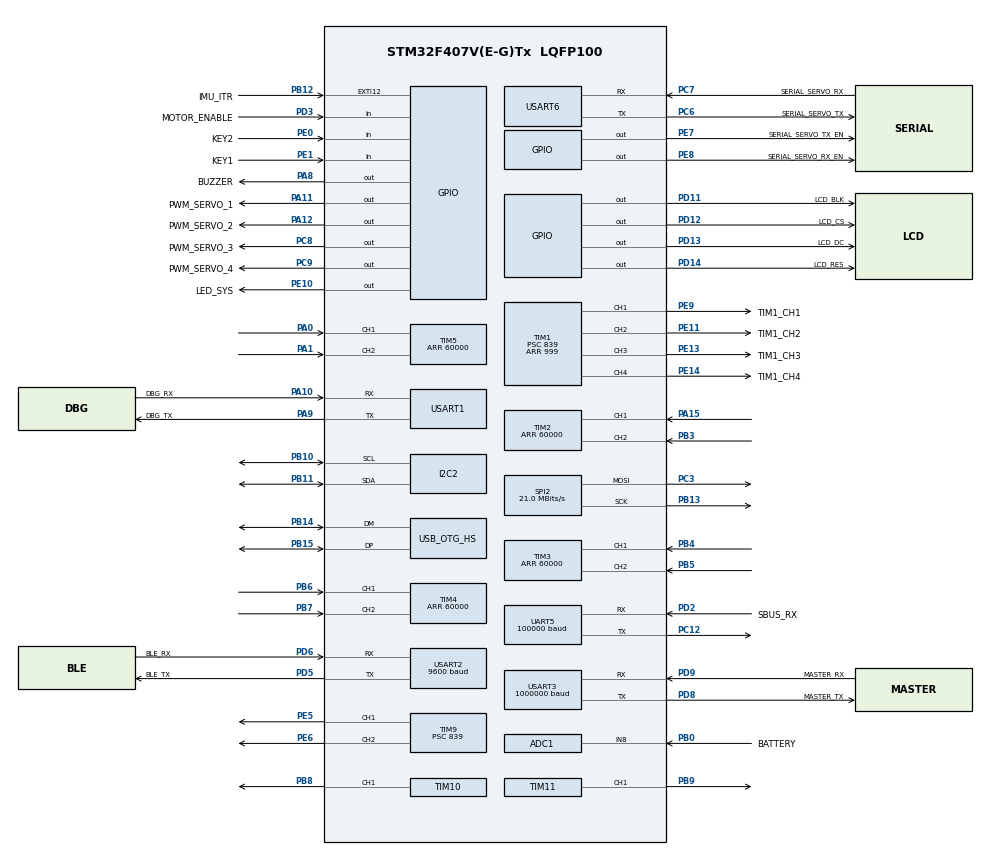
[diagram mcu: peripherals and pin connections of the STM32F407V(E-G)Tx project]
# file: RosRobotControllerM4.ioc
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ADC1.Channel-4\#ChannelRegularConversion=ADC_CHANNEL_VREFINT
ADC1.Channel-5\#ChannelRegularConversion=ADC_CHANNEL_8
ADC1.ClockPrescaler=ADC_CLOCK_SYNC_PCLK_DIV8
ADC1.ContinuousConvMode=DISABLE
ADC1.EOCSelection=ADC_EOC_SEQ_CONV
ADC1.NbrOfConversion=2
ADC1.NbrOfConversionFlag=1
ADC1.Rank-4\#ChannelRegularConversion=1
ADC1.Rank-5\#ChannelRegularConversion=2
ADC1.SamplingTime-4\#ChannelRegularConversion=ADC_SAMPLETIME_480CYCLES
ADC1.SamplingTime-5\#ChannelRegularConversion=ADC_SAMPLETIME_480CYCLES
ADC1.master=1
Dma.ADC1.8.Direction=DMA_PERIPH_TO_MEMORY
Dma.ADC1.8.FIFOMode=DMA_FIFOMODE_DISABLE
Dma.ADC1.8.Instance=DMA2_Stream0
Dma.ADC1.8.MemDataAlignment=DMA_MDATAALIGN_HALFWORD
Dma.ADC1.8.MemInc=DMA_MINC_ENABLE
Dma.ADC1.8.Mode=DMA_CIRCULAR
Dma.ADC1.8.PeriphDataAlignment=DMA_PDATAALIGN_HALFWORD
Dma.ADC1.8.PeriphInc=DMA_PINC_DISABLE
Dma.ADC1.8.Priority=DMA_PRIORITY_LOW
Dma.I2C2_RX.0.Direction=DMA_PERIPH_TO_MEMORY
Dma.I2C2_RX.0.FIFOMode=DMA_FIFOMODE_DISABLE
Dma.I2C2_RX.0.Instance=DMA1_Stream2
Dma.I2C2_RX.0.MemDataAlignment=DMA_MDATAALIGN_BYTE
Dma.I2C2_RX.0.MemInc=DMA_MINC_ENABLE
Dma.I2C2_RX.0.Mode=DMA_NORMAL
Dma.I2C2_RX.0.PeriphDataAlignment=DMA_PDATAALIGN_BYTE
Dma.I2C2_RX.0.PeriphInc=DMA_PINC_DISABLE
Dma.I2C2_RX.0.Priority=DMA_PRIORITY_VERY_HIGH
Dma.I2C2_TX.1.Direction=DMA_MEMORY_TO_PERIPH
Dma.I2C2_TX.1.FIFOMode=DMA_FIFOMODE_DISABLE
Dma.I2C2_TX.1.Instance=DMA1_Stream7
Dma.I2C2_TX.1.MemDataAlignment=DMA_MDATAALIGN_BYTE
Dma.I2C2_TX.1.MemInc=DMA_MINC_ENABLE
Dma.I2C2_TX.1.Mode=DMA_NORMAL
Dma.I2C2_TX.1.PeriphDataAlignment=DMA_PDATAALIGN_BYTE
Dma.I2C2_TX.1.PeriphInc=DMA_PINC_DISABLE
Dma.I2C2_TX.1.Priority=DMA_PRIORITY_VERY_HIGH
Dma.Request0=I2C2_RX
Dma.Request1=I2C2_TX
Dma.Request2=UART5_RX
Dma.Request3=USART3_RX
Dma.Request4=USART3_TX
Dma.Request5=SPI2_TX
Dma.Request6=USART2_RX
Dma.Request7=USART2_TX
Dma.Request8=ADC1
Dma.SPI2_TX.5.Direction=DMA_MEMORY_TO_PERIPH
Dma.SPI2_TX.5.FIFOMode=DMA_FIFOMODE_DISABLE
Dma.SPI2_TX.5.Instance=DMA1_Stream4
Dma.SPI2_TX.5.MemDataAlignment=DMA_MDATAALIGN_BYTE
Dma.SPI2_TX.5.MemInc=DMA_MINC_ENABLE
Dma.SPI2_TX.5.Mode=DMA_NORMAL
Dma.SPI2_TX.5.PeriphDataAlignment=DMA_PDATAALIGN_BYTE
Dma.SPI2_TX.5.PeriphInc=DMA_PINC_DISABLE
Dma.SPI2_TX.5.Priority=DMA_PRIORITY_LOW
Dma.UART5_RX.2.Direction=DMA_PERIPH_TO_MEMORY
Dma.UART5_RX.2.FIFOMode=DMA_FIFOMODE_DISABLE
Dma.UART5_RX.2.Instance=DMA1_Stream0
Dma.UART5_RX.2.MemDataAlignment=DMA_MDATAALIGN_BYTE
Dma.UART5_RX.2.MemInc=DMA_MINC_ENABLE
Dma.UART5_RX.2.Mode=DMA_CIRCULAR
Dma.UART5_RX.2.PeriphDataAlignment=DMA_PDATAALIGN_BYTE
Dma.UART5_RX.2.PeriphInc=DMA_PINC_DISABLE
Dma.UART5_RX.2.Priority=DMA_PRIORITY_MEDIUM
Dma.USART2_RX.6.Direction=DMA_PERIPH_TO_MEMORY
Dma.USART2_RX.6.FIFOMode=DMA_FIFOMODE_DISABLE
Dma.USART2_RX.6.Instance=DMA1_Stream5
Dma.USART2_RX.6.MemDataAlignment=DMA_MDATAALIGN_BYTE
Dma.USART2_RX.6.MemInc=DMA_MINC_ENABLE
Dma.USART2_RX.6.Mode=DMA_NORMAL
Dma.USART2_RX.6.PeriphDataAlignment=DMA_PDATAALIGN_BYTE
Dma.USART2_RX.6.PeriphInc=DMA_PINC_DISABLE
Dma.USART2_RX.6.Priority=DMA_PRIORITY_MEDIUM
Dma.USART2_TX.7.Direction=DMA_MEMORY_TO_PERIPH
Dma.USART2_TX.7.FIFOMode=DMA_FIFOMODE_DISABLE
Dma.USART2_TX.7.Instance=DMA1_Stream6
Dma.USART2_TX.7.MemDataAlignment=DMA_MDATAALIGN_BYTE
Dma.USART2_TX.7.MemInc=DMA_MINC_ENABLE
Dma.USART2_TX.7.Mode=DMA_NORMAL
Dma.USART2_TX.7.PeriphDataAlignment=DMA_PDATAALIGN_BYTE
Dma.USART2_TX.7.PeriphInc=DMA_PINC_DISABLE
Dma.USART2_TX.7.Priority=DMA_PRIORITY_MEDIUM
Dma.USART3_RX.3.Direction=DMA_PERIPH_TO_MEMORY
Dma.USART3_RX.3.FIFOMode=DMA_FIFOMODE_DISABLE
Dma.USART3_RX.3.Instance=DMA1_Stream1
Dma.USART3_RX.3.MemDataAlignment=DMA_MDATAALIGN_BYTE
Dma.USART3_RX.3.MemInc=DMA_MINC_ENABLE
Dma.USART3_RX.3.Mode=DMA_CIRCULAR
Dma.USART3_RX.3.PeriphDataAlignment=DMA_PDATAALIGN_BYTE
Dma.USART3_RX.3.PeriphInc=DMA_PINC_DISABLE
Dma.USART3_RX.3.Priority=DMA_PRIORITY_HIGH
Dma.USART3_TX.4.Direction=DMA_MEMORY_TO_PERIPH
Dma.USART3_TX.4.FIFOMode=DMA_FIFOMODE_DISABLE
Dma.USART3_TX.4.Instance=DMA1_Stream3
Dma.USART3_TX.4.MemDataAlignment=DMA_MDATAALIGN_BYTE
Dma.USART3_TX.4.MemInc=DMA_MINC_ENABLE
Dma.USART3_TX.4.Mode=DMA_NORMAL
Dma.USART3_TX.4.PeriphDataAlignment=DMA_PDATAALIGN_BYTE
Dma.USART3_TX.4.PeriphInc=DMA_PINC_DISABLE
Dma.USART3_TX.4.Priority=DMA_PRIORITY_HIGH
FREERTOS.BinarySemaphores01=packet_tx_idle,Static,packet_tx_ControlBlock;packet_rx_not_empty,Static,packet_rx_not_emptyControlBlock;mpu6050_data_ready,Static,mpu6050_data_readyControlBlock;sbus_data_ready_01_,Static,sbus_data_ready_01_ControlBlock;spi_tx_finished,Static,spi_tx_finishedControlBlock;bluetooth_tx_idle,Static,bluetooth_tx_idleControlBlock
FREERTOS.Events01=sbus_data_ready_event_,Static,sbus_data_ready_event_ControlBlock
FREERTOS.INCLUDE_vTaskCleanUpResources=1
FREERTOS.INCLUDE_xEventGroupSetBitFromISR=1
FREERTOS.Queues01=packet_tx_queue,64,void*,0,Static,packet_tx_queueBuffer,packet_tx_queueControlBlock;lvgl_event_queue,16,void*,0,Static,lvgl_event_queueBuffer,lvgl_event_queueControlBlock;moving_ctrl_queue,32,char,0,Static,moving_ctrl_queueBuffer,moving_ctrl_queueControlBlock;bluetooth_tx_queue,8,8,1,Static,bluetooth_tx_queueBuffer,bluetooth_tx_queueControlBlock
FREERTOS.Tasks01=defaultTask,8,128,StartDefaultTask,Default,NULL,Static,defaultTaskBuffer,defaultTaskControlBlock;imu_task,32,128,imu_task_entry,As weak,NULL,Static,imu_taskBuffer,imu_taskControlBlock;packet_tx_task,24,128,packet_tx_task_entry,As weak,NULL,Static,packet_tx_taskBuffer,packet_tx_taskControlBlock;packet_rx_task,24,256,packet_rx_task_entry,As weak,NULL,Static,packet_rx_taskBuffer,packet_rx_taskControlBlock;sbus_rx_task,24,128,sbus_rx_task_entry,As weak,NULL,Static,sbus_rx_taskBuffer,sbus_rx_taskControlBlock;gui_task,16,512,gui_task_entry,As weak,NULL,Static,gui_taskBuffer,gui_taskControlBlock;app_task,24,512,app_task_entry,As weak,NULL,Static,app_taskBuffer,app_taskControlBlock;bluetooth_task,24,128,bluetooth_task_entry,As weak,NULL,Static,bluetooth_taskBuffer,bluetooth_taskControlBlock
FREERTOS.Timers01=button_timer,button_timer_callback,osTimerPeriodic,As weak,NULL,Static,button_timerControlBlock;led_timer,led_timer_callback,osTimerPeriodic,As weak,NULL,Static,led_timerControlBlock;lvgl_timer,lvgl_timer_callback,osTimerPeriodic,As weak,NULL,Static,lvgl_timerControlBlock;buzzer_timer,buzzer_timer_callback,osTimerPeriodic,As weak,NULL,Static,buzzer_timerControlBlock;battery_check_timer,battery_check_timer_callback,osTimerPeriodic,As weak,NULL,Static,battery_check_timerControlBlock;IMU_read_timer,IMU_read_timer_callback,osTimerPeriodic,As weak,NULL,Static,IMU_read_timerControlBlock
FREERTOS.configENABLE_FPU=1
FREERTOS.configTIMER_QUEUE_LENGTH=10
FREERTOS.configTIMER_TASK_STACK_DEPTH=6144
FREERTOS.configTOTAL_HEAP_SIZE=12288
FREERTOS.configUSE_IDLE_HOOK=1
FREERTOS.configUSE_NEWLIB_REENTRANT=0
FREERTOS.configUSE_TICK_HOOK=1
I2C2.DutyCycle=I2C_DUTYCYCLE_16_9
I2C2.I2C_Mode=I2C_Fast
Mcu.Family=STM32F4
Mcu.Name=STM32F407V(E-G)Tx
Mcu.Package=LQFP100
NVIC.DMA1_Stream0_IRQn=true\:5\:0\:false\:true\:true\:1\:true\:false\:true\:true
NVIC.DMA1_Stream1_IRQn=true\:5\:0\:false\:true\:true\:2\:true\:false\:true\:true
NVIC.DMA1_Stream2_IRQn=true\:5\:0\:false\:true\:true\:3\:true\:false\:true\:true
NVIC.DMA1_Stream3_IRQn=true\:5\:0\:false\:true\:true\:4\:true\:false\:true\:true
NVIC.DMA1_Stream4_IRQn=true\:5\:0\:false\:false\:true\:true\:true\:true\:true
NVIC.DMA1_Stream5_IRQn=true\:5\:0\:false\:false\:true\:true\:true\:true\:true
NVIC.DMA1_Stream6_IRQn=true\:5\:0\:false\:false\:true\:true\:true\:true\:true
NVIC.DMA1_Stream7_IRQn=true\:5\:0\:false\:true\:true\:9\:true\:false\:true\:true
NVIC.EXTI15_10_IRQn=true\:5\:0\:false\:true\:true\:7\:true\:true\:false\:true
NVIC.OTG_HS_IRQn=true\:5\:0\:false\:false\:true\:true\:false\:true\:true
NVIC.PriorityGroup=NVIC_PRIORITYGROUP_4
NVIC.TIM2_IRQn=true\:5\:0\:false\:false\:true\:true\:true\:false\:true
NVIC.TIM3_IRQn=true\:5\:0\:false\:false\:true\:true\:true\:false\:true
NVIC.TIM4_IRQn=true\:5\:0\:false\:false\:true\:true\:true\:false\:true
NVIC.TIM5_IRQn=true\:5\:0\:false\:true\:true\:10\:true\:true\:false\:true
NVIC.TIM7_IRQn=true\:5\:0\:false\:true\:true\:12\:true\:true\:false\:true
NVIC.TIM8_BRK_TIM12_IRQn=true\:5\:0\:false\:false\:true\:true\:true\:false\:true
NVIC.TIM8_TRG_COM_TIM14_IRQn=true\:0\:0\:false\:false\:true\:false\:false\:true\:true
NVIC.TIM8_UP_TIM13_IRQn=true\:5\:0\:false\:true\:true\:8\:true\:true\:false\:true
NVIC.TimeBase=TIM8_TRG_COM_TIM14_IRQn
NVIC.TimeBaseIP=TIM14
NVIC.UART5_IRQn=true\:5\:0\:true\:true\:true\:11\:true\:true\:true\:true
NVIC.USART2_IRQn=true\:5\:0\:false\:true\:true\:5\:true\:true\:true\:true
NVIC.USART3_IRQn=true\:5\:0\:false\:true\:true\:6\:true\:true\:true\:true
NVIC.USART6_IRQn=true\:5\:0\:false\:true\:true\:13\:true\:true\:true\:true
PA0-WKUP.GPIO_PuPd=GPIO_PULLUP
PA0-WKUP.GPIO_Speed=GPIO_SPEED_FREQ_VERY_HIGH
PA0-WKUP.Signal=S_TIM5_CH1
PA1.GPIO_PuPd=GPIO_PULLUP
PA1.GPIO_Speed=GPIO_SPEED_FREQ_VERY_HIGH
PA1.Signal=S_TIM5_CH2
PA10.GPIO_Label=DBG_RX
PA10.Mode=Asynchronous
PA10.Signal=USART1_RX
PA11.GPIO_Label=PWM_SERVO_1
PA11.GPIO_Speed=GPIO_SPEED_FREQ_HIGH
PA11.PinState=GPIO_PIN_RESET
PA11.Signal=GPIO_Output
PA12.GPIO_Label=PWM_SERVO_2
PA12.GPIO_Speed=GPIO_SPEED_FREQ_HIGH
PA12.Signal=GPIO_Output
PA13.Signal=SYS_JTMS-SWDIO
PA14.Signal=SYS_JTCK-SWCLK
PA15.GPIO_PuPd=GPIO_PULLUP
PA15.GPIO_Speed=GPIO_SPEED_FREQ_VERY_HIGH
PA15.Signal=S_TIM2_CH1_ETR
PA8.GPIO_Label=BUZZER
PA8.GPIO_Speed=GPIO_SPEED_FREQ_VERY_HIGH
PA8.PinState=GPIO_PIN_RESET
PA8.Signal=GPIO_Output
PA9.GPIO_Label=DBG_TX
PA9.Mode=Asynchronous
PA9.Signal=USART1_TX
PB0.GPIO_Label=BATTERY
PB0.Signal=ADCx_IN8
PB10.GPIO_Pu=GPIO_PULLUP
PB10.Mode=I2C
PB10.Signal=I2C2_SCL
PB11.GPIO_Pu=GPIO_PULLUP
PB11.Mode=I2C
PB11.Signal=I2C2_SDA
PB12.GPIO_Label=IMU_ITR
PB12.Signal=GPXTI12
PB13.Mode=TX_Only_Simplex_Unidirect_Master
PB13.Signal=SPI2_SCK
PB14.Mode=Host_FS
PB14.Signal=USB_OTG_HS_DM
PB15.Mode=Host_FS
PB15.Signal=USB_OTG_HS_DP
PB3.GPIO_PuPd=GPIO_PULLUP
PB3.GPIO_Speed=GPIO_SPEED_FREQ_VERY_HIGH
PB3.Signal=S_TIM2_CH2
PB4.GPIO_Speed=GPIO_SPEED_FREQ_VERY_HIGH
PB4.Signal=S_TIM3_CH1
PB5.GPIO_Speed=GPIO_SPEED_FREQ_VERY_HIGH
PB5.Signal=S_TIM3_CH2
PB6.Signal=S_TIM4_CH1
PB7.Signal=S_TIM4_CH2
PB8.Signal=S_TIM10_CH1
PB9.GPIO_Speed=GPIO_SPEED_FREQ_HIGH
PB9.Signal=S_TIM11_CH1
PC12.Mode=Asynchronous
PC12.Signal=UART5_TX
PC3.Mode=TX_Only_Simplex_Unidirect_Master
PC3.Signal=SPI2_MOSI
PC6.GPIO_Label=SERIAL_SERVO_TX
PC6.Mode=Asynchronous
PC6.Signal=USART6_TX
PC7.GPIO_Label=SERIAL_SERVO_RX
PC7.Mode=Asynchronous
PC7.Signal=USART6_RX
PC8.GPIO_Label=PWM_SERVO_3
PC8.GPIO_Speed=GPIO_SPEED_FREQ_HIGH
PC8.PinState=GPIO_PIN_SET
PC8.Signal=GPIO_Output
PC9.GPIO_Label=PWM_SERVO_4
PC9.GPIO_Speed=GPIO_SPEED_FREQ_HIGH
PC9.Signal=GPIO_Output
PD11.GPIO_Label=LCD_BLK
PD11.GPIO_Speed=GPIO_SPEED_FREQ_VERY_HIGH
PD11.PinState=GPIO_PIN_SET
PD11.Signal=GPIO_Output
PD12.GPIO_Label=LCD_CS
PD12.GPIO_Speed=GPIO_SPEED_FREQ_VERY_HIGH
PD12.PinState=GPIO_PIN_SET
PD12.Signal=GPIO_Output
PD13.GPIO_Label=LCD_DC
PD13.GPIO_Speed=GPIO_SPEED_FREQ_VERY_HIGH
PD13.Signal=GPIO_Output
PD14.GPIO_Label=LCD_RES
PD14.GPIO_Speed=GPIO_SPEED_FREQ_VERY_HIGH
PD14.PinState=GPIO_PIN_SET
PD14.Signal=GPIO_Output
PD2.GPIO_Label=SBUS_RX
PD2.Mode=Asynchronous
PD2.Signal=UART5_RX
PD3.GPIO_Label=MOTOR_ENABLE
PD3.Signal=GPIO_Input
PD5.GPIO_Label=BLE_TX
PD5.Mode=Asynchronous
PD5.Signal=USART2_TX
PD6.GPIO_Label=BLE_RX
PD6.Mode=Asynchronous
PD6.Signal=USART2_RX
PD8.GPIO_Label=MASTER_TX
PD8.GPIO_PuPd=GPIO_NOPULL
PD8.Mode=Asynchronous
PD8.Signal=USART3_TX
PD9.GPIO_Label=MASTER_RX
PD9.GPIO_PuPd=GPIO_NOPULL
PD9.Mode=Asynchronous
PD9.Signal=USART3_RX
PE0.GPIO_Label=KEY2
PE0.Signal=GPIO_Input
PE1.GPIO_Label=KEY1
PE1.Signal=GPIO_Input
PE10.GPIO_Label=LED_SYS
PE10.GPIO_Speed=GPIO_SPEED_FREQ_MEDIUM
PE10.PinState=GPIO_PIN_SET
PE10.Signal=GPIO_Output
PE11.GPIO_Label=TIM1_CH2
PE11.GPIO_Speed=GPIO_SPEED_FREQ_HIGH
PE11.Signal=S_TIM1_CH2
PE13.GPIO_Label=TIM1_CH3
PE13.GPIO_Speed=GPIO_SPEED_FREQ_HIGH
PE13.Signal=S_TIM1_CH3
PE14.GPIO_Label=TIM1_CH4
PE14.GPIO_Speed=GPIO_SPEED_FREQ_HIGH
PE14.Signal=S_TIM1_CH4
PE5.Signal=S_TIM9_CH1
PE6.Signal=S_TIM9_CH2
PE7.GPIO_Label=SERIAL_SERVO_TX_EN
PE7.GPIO_Speed=GPIO_SPEED_FREQ_VERY_HIGH
PE7.Signal=GPIO_Output
PE8.GPIO_Label=SERIAL_SERVO_RX_EN
PE8.GPIO_Speed=GPIO_SPEED_FREQ_VERY_HIGH
PE8.Signal=GPIO_Output
PE9.GPIO_Label=TIM1_CH1
PE9.GPIO_Speed=GPIO_SPEED_FREQ_HIGH
PE9.Signal=S_TIM1_CH1
PH0-OSC_IN.Mode=HSE-External-Oscillator
PH0-OSC_IN.Signal=RCC_OSC_IN
PH1-OSC_OUT.Mode=HSE-External-Oscillator
PH1-OSC_OUT.Signal=RCC_OSC_OUT
ProjectManager.HeapSize=0x200
ProjectManager.StackSize=0x600
ProjectManager.TargetToolchain=STM32CubeIDE
RCC.48MHZClocksFreq_Value=48000000
RCC.AHBFreq_Value=168000000
RCC.APB1CLKDivider=RCC_HCLK_DIV4
RCC.APB1Freq_Value=42000000
RCC.APB1TimFreq_Value=84000000
RCC.APB2CLKDivider=RCC_HCLK_DIV2
RCC.APB2Freq_Value=84000000
RCC.APB2TimFreq_Value=168000000
RCC.CortexFreq_Value=168000000
RCC.EnbaleCSS=true
RCC.HCLKFreq_Value=168000000
RCC.HSE_VALUE=8000000
RCC.HSI_VALUE=16000000
RCC.LSE_VALUE=32768
RCC.PLLM=4
RCC.PLLN=168
RCC.PLLQ=7
RCC.SYSCLKFreq_VALUE=168000000
RCC.SYSCLKSource=RCC_SYSCLKSOURCE_PLLCLK
RCC.VCOOutputFreq_Value=336000000
SH.ADCx_IN8.0=ADC1_IN8,IN8
SH.S_TIM10_CH1.0=TIM10_CH1,PWM Generation1 CH1
SH.S_TIM11_CH1.0=TIM11_CH1,PWM Generation1 CH1
SH.S_TIM1_CH1.0=TIM1_CH1,PWM Generation1 CH1
SH.S_TIM1_CH2.0=TIM1_CH2,PWM Generation2 CH2
SH.S_TIM1_CH3.0=TIM1_CH3,PWM Generation3 CH3
SH.S_TIM1_CH4.0=TIM1_CH4,PWM Generation4 CH4
SH.S_TIM2_CH1_ETR.0=TIM2_CH1,Encoder_Interface
SH.S_TIM2_CH2.0=TIM2_CH2,Encoder_Interface
SH.S_TIM3_CH1.0=TIM3_CH1,Encoder_Interface
SH.S_TIM3_CH2.0=TIM3_CH2,Encoder_Interface
SH.S_TIM4_CH1.0=TIM4_CH1,Encoder_Interface
SH.S_TIM4_CH2.0=TIM4_CH2,Encoder_Interface
SH.S_TIM5_CH1.0=TIM5_CH1,Encoder_Interface
SH.S_TIM5_CH2.0=TIM5_CH2,Encoder_Interface
SH.S_TIM9_CH1.0=TIM9_CH1,PWM Generation1 CH1
SH.S_TIM9_CH2.0=TIM9_CH2,PWM Generation2 CH2
SPI2.BaudRatePrescaler=SPI_BAUDRATEPRESCALER_2
SPI2.CLKPhase=SPI_PHASE_1EDGE
SPI2.CLKPolarity=SPI_POLARITY_LOW
SPI2.CalculateBaudRate=21.0 MBits/s
SPI2.DataSize=SPI_DATASIZE_8BIT
SPI2.Direction=SPI_DIRECTION_2LINES
SPI2.FirstBit=SPI_FIRSTBIT_MSB
SPI2.Mode=SPI_MODE_MASTER
SPI2.VirtualType=VM_MASTER
TIM1.AutoReloadPreload=TIM_AUTORELOAD_PRELOAD_ENABLE
TIM1.Channel-PWM\ Generation1\ CH1=TIM_CHANNEL_1
TIM1.Channel-PWM\ Generation2\ CH2=TIM_CHANNEL_2
TIM1.Channel-PWM\ Generation3\ CH3=TIM_CHANNEL_3
TIM1.Channel-PWM\ Generation4\ CH4=TIM_CHANNEL_4
TIM1.OCFastMode_PWM-PWM\ Generation1\ CH1=TIM_OCFAST_ENABLE
TIM1.OCFastMode_PWM-PWM\ Generation2\ CH2=TIM_OCFAST_ENABLE
TIM1.OCFastMode_PWM-PWM\ Generation3\ CH3=TIM_OCFAST_ENABLE
TIM1.OCFastMode_PWM-PWM\ Generation4\ CH4=TIM_OCFAST_ENABLE
TIM1.Period=999
TIM1.Prescaler=839
TIM1.Pulse-PWM\ Generation1\ CH1=0
TIM1.Pulse-PWM\ Generation2\ CH2=0
TIM1.Pulse-PWM\ Generation3\ CH3=0
TIM1.Pulse-PWM\ Generation4\ CH4=0
TIM10.AutoReloadPreload=TIM_AUTORELOAD_PRELOAD_ENABLE
TIM10.Channel=TIM_CHANNEL_1
TIM10.OCFastMode_PWM=TIM_OCFAST_ENABLE
TIM10.Period=999
TIM10.Prescaler=839
TIM11.AutoReloadPreload=TIM_AUTORELOAD_PRELOAD_ENABLE
TIM11.Channel=TIM_CHANNEL_1
TIM11.OCFastMode_PWM=TIM_OCFAST_ENABLE
TIM11.Period=999
TIM11.Prescaler=839
TIM11.Pulse=0
TIM12.AutoReloadPreload=TIM_AUTORELOAD_PRELOAD_ENABLE
TIM12.Channel-Output\ Compare1\ No\ Output=TIM_CHANNEL_1
TIM12.OC1Preload=ENABLE
TIM12.OCMode_1=TIM_OCMODE_TIMING
TIM12.Period=99
TIM12.Prescaler=839
TIM12.Pulse-Output\ Compare1\ No\ Output=50
TIM13.AutoReloadPreload=TIM_AUTORELOAD_PRELOAD_ENABLE
TIM13.Channel=TIM_CHANNEL_1
TIM13.OC1Preload=DISABLE
TIM13.Period=4999
TIM13.Prescaler=83
TIM13.Pulse=0
TIM2.AutoReloadPreload=TIM_AUTORELOAD_PRELOAD_ENABLE
TIM2.EncoderMode=TIM_ENCODERMODE_TI12
TIM2.Period=60000
TIM3.AutoReloadPreload=TIM_AUTORELOAD_PRELOAD_ENABLE
TIM3.EncoderMode=TIM_ENCODERMODE_TI12
TIM3.Period=60000
TIM4.AutoReloadPreload=TIM_AUTORELOAD_PRELOAD_ENABLE
TIM4.EncoderMode=TIM_ENCODERMODE_TI12
TIM4.Period=60000
TIM5.AutoReloadPreload=TIM_AUTORELOAD_PRELOAD_ENABLE
TIM5.EncoderMode=TIM_ENCODERMODE_TI12
TIM5.Period=60000
TIM7.AutoReloadPreload=TIM_AUTORELOAD_PRELOAD_ENABLE
TIM7.Period=9999
TIM7.Prescaler=83
TIM9.AutoReloadPreload=TIM_AUTORELOAD_PRELOAD_ENABLE
TIM9.Channel-PWM\ Generation1\ CH1=TIM_CHANNEL_1
TIM9.Channel-PWM\ Generation2\ CH2=TIM_CHANNEL_2
TIM9.OCFastMode_PWM-PWM\ Generation1\ CH1=TIM_OCFAST_ENABLE
TIM9.OCFastMode_PWM-PWM\ Generation2\ CH2=TIM_OCFAST_ENABLE
TIM9.Period=999
TIM9.Prescaler=839
UART5.BaudRate=100000
UART5.Mode=MODE_RX
UART5.Parity=PARITY_EVEN
UART5.StopBits=UART_STOPBITS_2
UART5.VirtualMode=Asynchronous
UART5.WordLength=WORDLENGTH_9B
USART1.VirtualMode=VM_ASYNC
USART2.BaudRate=9600
USART2.VirtualMode=VM_ASYNC
USART3.BaudRate=1000000
USART3.VirtualMode=VM_ASYNC
USART6.VirtualMode=VM_ASYNC
USB_HOST.USBH_DEBUG_LEVEL-HID_HS=0
USB_HOST.USBH_HandleTypeDef-HID_HS=hUsbHostHS
USB_HOST.USBH_KEEP_CFG_DESCRIPTOR-HID_HS=1
USB_HOST.USBH_MAX_DATA_BUFFER-HID_HS=512
USB_HOST.USBH_MAX_NUM_CONFIGURATION-HID_HS=2
USB_HOST.USBH_MAX_NUM_ENDPOINTS-HID_HS=2
USB_HOST.USBH_MAX_NUM_INTERFACES-HID_HS=2
USB_HOST.USBH_MAX_NUM_SUPPORTED_CLASS-HID_HS=1
USB_HOST.USBH_MAX_SIZE_CONFIGURATION-HID_HS=512
USB_HOST.USBH_PROCESS_PRIO-HID_HS=osPriorityNormal
USB_HOST.USBH_PROCESS_STACK_SIZE-HID_HS=2048
USB_HOST.VirtualModeHS=Hid
USB_OTG_HS.Sof_enable-Host_FS=DISABLE
USB_OTG_HS.VirtualMode-Host_FS=Host_FS
USB_OTG_HS.dma_enable-Host_FS=DISABLE
VP_ADC1_Vref_Input.Mode=IN-Vrefint
VP_CRC_VS_CRC.Mode=CRC_Activate
VP_FREERTOS_VS_CMSIS_V2.Mode=CMSIS_V2
VP_SYS_VS_tim14.Mode=TIM14
VP_TIM10_VS_ClockSourceINT.Mode=Enable_Timer
VP_TIM11_VS_ClockSourceINT.Mode=Enable_Timer
VP_TIM12_VS_ClockSourceINT.Mode=Internal
VP_TIM12_VS_no_output1.Mode=Output Compare1 No Output
VP_TIM13_VS_ClockSourceINT.Mode=Enable_Timer
VP_TIM13_VS_no_output1.Mode=Output Compare1 No Output
VP_TIM1_VS_ClockSourceINT.Mode=Internal
VP_TIM7_VS_ClockSourceINT.Mode=Enable_Timer
VP_TIM9_VS_ClockSourceINT.Mode=Internal
VP_USB_HOST_VS_USB_HOST_HID_HS.Mode=HID_HS
board=custom

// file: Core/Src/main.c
/* USER CODE BEGIN Header */
/**
  ******************************************************************************
  * @file           : main.c
  * @brief          : Main program body
  ******************************************************************************
  * @attention
  *
  * <h2><center>&copy; Copyright (c) 2023 STMicroelectronics.
  * All rights reserved.</center></h2>
  *
  * This software component is licensed by ST under BSD 3-Clause license,
  * the "License"; You may not use this file except in compliance with the
  * License. You may obtain a copy of the License at:
  *                        opensource.org/licenses/BSD-3-Clause
  *
  * ********************************************
  *   main()函数，单片机入口函数
  *
  *   ! ! ! 注意
  *   该工程使用了 FreeRTOS系统
  *   用户的入口函数在 Hiwonder/System文件夹中的app.c文件中的app_task_entry()线程任务�?
  *   �?要其他线程任务，则需创建其他线程（建议在STM32CubeMX软件中创建）
  *
  *   ! ! ! 注意
  *   在CubeMX中创建的文件中，
  *   用户程序与注�? 都需要写在以下注释的中间，才不会在使用CubeMX更改配置之后，导致用户程序被覆盖�? !!!
  *   (若不使用CubeMX软件，则可跳过该�?)
  *
  *   / * USER CODE BEGIN xxx * /
  *   //用户程序
  *   / * USER CODE END xxx * /
  *
  *
  * ********************************************
  *
  ******************************************************************************
  */
/* USER CODE END Header */
#include "main.h"
#include "cmsis_os.h"
#include "adc.h"
#include "crc.h"
#include "dma.h"
#include "i2c.h"
#include "spi.h"
#include "tim.h"
#include "usart.h"
#include "usb_host.h"
#include "gpio.h"

/* USER CODE BEGIN Includes */
#include "lwmem_porting.h"
#include "log.h"
#include <stdio.h>
/* USER CODE END Includes */

void SystemClock_Config(void);
void MX_FREERTOS_Init(void);
static void MX_NVIC_Init(void);

int main(void)
{
  /* USER CODE BEGIN 1 */
  //��־��ӡ���ܳ�ʼ��
  LOG_INIT();
  lwmem_assignmem(lwmem_regions);  /* ��̬�ڴ��ʼ�� */
  /* USER CODE END 1 */

  /* MCU Configuration--------------------------------------------------------*/

  /* Reset of all peripherals, Initializes the Flash interface and the Systick. */
  HAL_Init();

  /* Configure the system clock */
  SystemClock_Config();

  /* USER CODE BEGIN SysInit */
    //����IIC1
    __HAL_RCC_I2C1_CLK_ENABLE();
    //����DMA����
    __HAL_RCC_DMA1_CLK_ENABLE();
  /* USER CODE END SysInit */

  /* Initialize all configured peripherals */
  MX_GPIO_Init();
  MX_DMA_Init();
  MX_USART1_UART_Init();
  MX_SPI2_Init();
  MX_TIM1_Init();
  MX_TIM2_Init();
  MX_TIM5_Init();
  MX_TIM9_Init();
  MX_TIM10_Init();
  MX_TIM11_Init();
  MX_I2C2_Init();
  MX_UART5_Init();
  MX_USART2_UART_Init();
  MX_USART3_UART_Init();
  MX_USART6_UART_Init();
  MX_TIM7_Init();
  MX_TIM3_Init();
  MX_TIM4_Init();
  MX_TIM13_Init();
  MX_CRC_Init();
  MX_TIM12_Init();
  MX_ADC1_Init();

  // 1. USB 전원 공급용 유력 후보 핀들을 출력으로 설정
  GPIO_InitTypeDef GPIO_InitStruct = {0};
  __HAL_RCC_GPIOC_CLK_ENABLE();
  __HAL_RCC_GPIOH_CLK_ENABLE();

  MX_USB_HOST_Init();

  /* Initialize interrupts */
  MX_NVIC_Init();
  /* USER CODE BEGIN 2 */
  //��ӡ��Ϣ����printf()�������÷�һ�����ܹ����ݵȼ�����������־���
  LOG_DEBUG("Start...\r\n");
  /* USER CODE END 2 */

  /* Init scheduler */
  osKernelInitialize();  /* Call init function for freertos objects (in freertos.c) */
  MX_FREERTOS_Init();

  /* Start scheduler */
  osKernelStart();
  /* We should never get here as control is now taken by the scheduler */
  /* Infinite loop */
    while (1) {

    }
}

void SystemClock_Config(void)
{
  RCC_OscInitTypeDef RCC_OscInitStruct = {0};
  RCC_ClkInitTypeDef RCC_ClkInitStruct = {0};

  /** Configure the main internal regulator output voltage
  */
  __HAL_RCC_PWR_CLK_ENABLE();
  __HAL_PWR_VOLTAGESCALING_CONFIG(PWR_REGULATOR_VOLTAGE_SCALE1);

  /** Initializes the RCC Oscillators according to the specified parameters
  * in the RCC_OscInitTypeDef structure.
  */
  RCC_OscInitStruct.OscillatorType = RCC_OSCILLATORTYPE_HSE;
  RCC_OscInitStruct.HSEState = RCC_HSE_ON;
  RCC_OscInitStruct.PLL.PLLState = RCC_PLL_ON;
  RCC_OscInitStruct.PLL.PLLSource = RCC_PLLSOURCE_HSE;
  RCC_OscInitStruct.PLL.PLLM = 6;
  RCC_OscInitStruct.PLL.PLLN = 168;
  RCC_OscInitStruct.PLL.PLLP = RCC_PLLP_DIV2;
  RCC_OscInitStruct.PLL.PLLQ = 7;
  if (HAL_RCC_OscConfig(&RCC_OscInitStruct) != HAL_OK)
  {
    Error_Handler();
  }

  /** Initializes the CPU, AHB and APB buses clocks
  */
  RCC_ClkInitStruct.ClockType = RCC_CLOCKTYPE_HCLK|RCC_CLOCKTYPE_SYSCLK
                              |RCC_CLOCKTYPE_PCLK1|RCC_CLOCKTYPE_PCLK2;
  RCC_ClkInitStruct.SYSCLKSource = RCC_SYSCLKSOURCE_PLLCLK;
  RCC_ClkInitStruct.AHBCLKDivider = RCC_SYSCLK_DIV1;
  RCC_ClkInitStruct.APB1CLKDivider = RCC_HCLK_DIV4;
  RCC_ClkInitStruct.APB2CLKDivider = RCC_HCLK_DIV2;

  if (HAL_RCC_ClockConfig(&RCC_ClkInitStruct, FLASH_LATENCY_5) != HAL_OK)
  {
    Error_Handler();
  }

  /** Enables the Clock Security System
  */
  HAL_RCC_EnableCSS();
}

/**
  * @brief NVIC Configuration.
  * @retval None
  */
static void MX_NVIC_Init(void)
{
  /* DMA1_Stream0_IRQn interrupt configuration */
  HAL_NVIC_SetPriority(DMA1_Stream0_IRQn, 5, 0);
  HAL_NVIC_EnableIRQ(DMA1_Stream0_IRQn);
  /* DMA1_Stream1_IRQn interrupt configuration */
  HAL_NVIC_SetPriority(DMA1_Stream1_IRQn, 5, 0);
  HAL_NVIC_EnableIRQ(DMA1_Stream1_IRQn);
  /* DMA1_Stream2_IRQn interrupt configuration */
  HAL_NVIC_SetPriority(DMA1_Stream2_IRQn, 5, 0);
  HAL_NVIC_EnableIRQ(DMA1_Stream2_IRQn);
  /* DMA1_Stream3_IRQn interrupt configuration */
  HAL_NVIC_SetPriority(DMA1_Stream3_IRQn, 5, 0);
  HAL_NVIC_EnableIRQ(DMA1_Stream3_IRQn);
  /* USART2_IRQn interrupt configuration */
  HAL_NVIC_SetPriority(USART2_IRQn, 5, 0);
  HAL_NVIC_EnableIRQ(USART2_IRQn);
  /* USART3_IRQn interrupt configuration */
  HAL_NVIC_SetPriority(USART3_IRQn, 5, 0);
  HAL_NVIC_EnableIRQ(USART3_IRQn);
  /* EXTI15_10_IRQn interrupt configuration */
  HAL_NVIC_SetPriority(EXTI15_10_IRQn, 5, 0);
  HAL_NVIC_EnableIRQ(EXTI15_10_IRQn);
  /* TIM8_UP_TIM13_IRQn interrupt configuration */
  HAL_NVIC_SetPriority(TIM8_UP_TIM13_IRQn, 5, 0);
  HAL_NVIC_EnableIRQ(TIM8_UP_TIM13_IRQn);
  /* DMA1_Stream7_IRQn interrupt configuration */
  HAL_NVIC_SetPriority(DMA1_Stream7_IRQn, 5, 0);
  HAL_NVIC_EnableIRQ(DMA1_Stream7_IRQn);
  /* TIM5_IRQn interrupt configuration */
  HAL_NVIC_SetPriority(TIM5_IRQn, 5, 0);
  HAL_NVIC_EnableIRQ(TIM5_IRQn);
  /* UART5_IRQn interrupt configuration */
  HAL_NVIC_SetPriority(UART5_IRQn, 5, 0);
  HAL_NVIC_EnableIRQ(UART5_IRQn);
  /* TIM7_IRQn interrupt configuration */
  HAL_NVIC_SetPriority(TIM7_IRQn, 5, 0);
  HAL_NVIC_EnableIRQ(TIM7_IRQn);
  /* USART6_IRQn interrupt configuration */
  HAL_NVIC_SetPriority(USART6_IRQn, 5, 0);
  HAL_NVIC_EnableIRQ(USART6_IRQn);
}

void HAL_TIM_PeriodElapsedCallback(TIM_HandleTypeDef *htim)
{
  if (htim->Instance == TIM14) {
    HAL_IncTick();
  }
}

void Error_Handler(void)
{
    __disable_irq();
    while (1) {
    }
}

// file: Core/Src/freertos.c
/* USER CODE BEGIN Header */
/**
  ******************************************************************************
  * File Name          : freertos.c
  * Description        : Code for freertos applications
  ******************************************************************************
  * @attention
  *
  * <h2><center>&copy; Copyright (c) 2023 STMicroelectronics.
  * All rights reserved.</center></h2>
  *
  * This software component is licensed by ST under Ultimate Liberty license
  * SLA0044, the "License"; You may not use this file except in compliance with
  * the License. You may obtain a copy of the License at:
  *                             www.st.com/SLA0044
  *
  ******************************************************************************
  */
/* USER CODE END Header */

#include "FreeRTOS.h"
#include "task.h"
#include "main.h"
#include "cmsis_os.h"

/* USER CODE BEGIN Includes */
#include "lvgl.h"
/* USER CODE END Includes */

typedef StaticTask_t osStaticThreadDef_t;
typedef StaticQueue_t osStaticMessageQDef_t;
typedef StaticTimer_t osStaticTimerDef_t;
typedef StaticEventGroup_t osStaticEventGroupDef_t;

/* Definitions for defaultTask */
osThreadId_t defaultTaskHandle;
uint32_t defaultTaskBuffer[ 128 ];
osStaticThreadDef_t defaultTaskControlBlock;
const osThreadAttr_t defaultTask_attributes = {
  .name = "defaultTask",
  .cb_mem = &defaultTaskControlBlock,
  .cb_size = sizeof(defaultTaskControlBlock),
  .stack_mem = &defaultTaskBuffer[0],
  .stack_size = sizeof(defaultTaskBuffer),
  .priority = (osPriority_t) osPriorityLow,
};
/* Definitions for imu_task */
osThreadId_t imu_taskHandle;
uint32_t imu_taskBuffer[ 128 ];
osStaticThreadDef_t imu_taskControlBlock;
const osThreadAttr_t imu_task_attributes = {
  .name = "imu_task",
  .cb_mem = &imu_taskControlBlock,
  .cb_size = sizeof(imu_taskControlBlock),
  .stack_mem = &imu_taskBuffer[0],
  .stack_size = sizeof(imu_taskBuffer),
  .priority = (osPriority_t) osPriorityAboveNormal,
};
/* Definitions for packet_tx_task */
osThreadId_t packet_tx_taskHandle;
uint32_t packet_tx_taskBuffer[ 128 ];
osStaticThreadDef_t packet_tx_taskControlBlock;
const osThreadAttr_t packet_tx_task_attributes = {
  .name = "packet_tx_task",
  .cb_mem = &packet_tx_taskControlBlock,
  .cb_size = sizeof(packet_tx_taskControlBlock),
  .stack_mem = &packet_tx_taskBuffer[0],
  .stack_size = sizeof(packet_tx_taskBuffer),
  .priority = (osPriority_t) osPriorityNormal,
};
/* Definitions for packet_rx_task */
osThreadId_t packet_rx_taskHandle;
uint32_t packet_rx_taskBuffer[ 256 ];
osStaticThreadDef_t packet_rx_taskControlBlock;
const osThreadAttr_t packet_rx_task_attributes = {
  .name = "packet_rx_task",
  .cb_mem = &packet_rx_taskControlBlock,
  .cb_size = sizeof(packet_rx_taskControlBlock),
  .stack_mem = &packet_rx_taskBuffer[0],
  .stack_size = sizeof(packet_rx_taskBuffer),
  .priority = (osPriority_t) osPriorityNormal,
};
/* Definitions for sbus_rx_task */
osThreadId_t sbus_rx_taskHandle;
uint32_t sbus_rx_taskBuffer[ 128 ];
osStaticThreadDef_t sbus_rx_taskControlBlock;
const osThreadAttr_t sbus_rx_task_attributes = {
  .name = "sbus_rx_task",
  .cb_mem = &sbus_rx_taskControlBlock,
  .cb_size = sizeof(sbus_rx_taskControlBlock),
  .stack_mem = &sbus_rx_taskBuffer[0],
  .stack_size = sizeof(sbus_rx_taskBuffer),
  .priority = (osPriority_t) osPriorityNormal,
};
/* Definitions for gui_task */
osThreadId_t gui_taskHandle;
uint32_t gui_taskBuffer[ 512 ];
osStaticThreadDef_t gui_taskControlBlock;
const osThreadAttr_t gui_task_attributes = {
  .name = "gui_task",
  .cb_mem = &gui_taskControlBlock,
  .cb_size = sizeof(gui_taskControlBlock),
  .stack_mem = &gui_taskBuffer[0],
  .stack_size = sizeof(gui_taskBuffer),
  .priority = (osPriority_t) osPriorityBelowNormal,
};
/* Definitions for app_task */
osThreadId_t app_taskHandle;
uint32_t app_taskBuffer[ 512 ];
osStaticThreadDef_t app_taskControlBlock;
const osThreadAttr_t app_task_attributes = {
  .name = "app_task",
  .cb_mem = &app_taskControlBlock,
  .cb_size = sizeof(app_taskControlBlock),
  .stack_mem = &app_taskBuffer[0],
  .stack_size = sizeof(app_taskBuffer),
  .priority = (osPriority_t) osPriorityNormal,
};
/* Definitions for bluetooth_task */
osThreadId_t bluetooth_taskHandle;
uint32_t bluetooth_taskBuffer[ 128 ];
osStaticThreadDef_t bluetooth_taskControlBlock;
const osThreadAttr_t bluetooth_task_attributes = {
  .name = "bluetooth_task",
  .cb_mem = &bluetooth_taskControlBlock,
  .cb_size = sizeof(bluetooth_taskControlBlock),
  .stack_mem = &bluetooth_taskBuffer[0],
  .stack_size = sizeof(bluetooth_taskBuffer),
  .priority = (osPriority_t) osPriorityNormal,
};
/* Definitions for packet_tx_queue */
osMessageQueueId_t packet_tx_queueHandle;
uint8_t packet_tx_queueBuffer[ 64 * sizeof( void* ) ];
osStaticMessageQDef_t packet_tx_queueControlBlock;
const osMessageQueueAttr_t packet_tx_queue_attributes = {
  .name = "packet_tx_queue",
  .cb_mem = &packet_tx_queueControlBlock,
  .cb_size = sizeof(packet_tx_queueControlBlock),
  .mq_mem = &packet_tx_queueBuffer,
  .mq_size = sizeof(packet_tx_queueBuffer)
};
/* Definitions for lvgl_event_queue */
osMessageQueueId_t lvgl_event_queueHandle;
uint8_t lvgl_event_queueBuffer[ 16 * sizeof( void* ) ];
osStaticMessageQDef_t lvgl_event_queueControlBlock;
const osMessageQueueAttr_t lvgl_event_queue_attributes = {
  .name = "lvgl_event_queue",
  .cb_mem = &lvgl_event_queueControlBlock,
  .cb_size = sizeof(lvgl_event_queueControlBlock),
  .mq_mem = &lvgl_event_queueBuffer,
  .mq_size = sizeof(lvgl_event_queueBuffer)
};
/* Definitions for moving_ctrl_queue */
osMessageQueueId_t moving_ctrl_queueHandle;
uint8_t moving_ctrl_queueBuffer[ 32 * sizeof( char ) ];
osStaticMessageQDef_t moving_ctrl_queueControlBlock;
const osMessageQueueAttr_t moving_ctrl_queue_attributes = {
  .name = "moving_ctrl_queue",
  .cb_mem = &moving_ctrl_queueControlBlock,
  .cb_size = sizeof(moving_ctrl_queueControlBlock),
  .mq_mem = &moving_ctrl_queueBuffer,
  .mq_size = sizeof(moving_ctrl_queueBuffer)
};
/* Definitions for bluetooth_tx_queue */
osMessageQueueId_t bluetooth_tx_queueHandle;
uint8_t bluetooth_tx_queueBuffer[ 8 * 8 ];
osStaticMessageQDef_t bluetooth_tx_queueControlBlock;
const osMessageQueueAttr_t bluetooth_tx_queue_attributes = {
  .name = "bluetooth_tx_queue",
  .cb_mem = &bluetooth_tx_queueControlBlock,
  .cb_size = sizeof(bluetooth_tx_queueControlBlock),
  .mq_mem = &bluetooth_tx_queueBuffer,
  .mq_size = sizeof(bluetooth_tx_queueBuffer)
};
/* Definitions for button_timer */
osTimerId_t button_timerHandle;
osStaticTimerDef_t button_timerControlBlock;
const osTimerAttr_t button_timer_attributes = {
  .name = "button_timer",
  .cb_mem = &button_timerControlBlock,
  .cb_size = sizeof(button_timerControlBlock),
};
/* Definitions for led_timer */
osTimerId_t led_timerHandle;
osStaticTimerDef_t led_timerControlBlock;
const osTimerAttr_t led_timer_attributes = {
  .name = "led_timer",
  .cb_mem = &led_timerControlBlock,
  .cb_size = sizeof(led_timerControlBlock),
};
/* Definitions for lvgl_timer */
osTimerId_t lvgl_timerHandle;
osStaticTimerDef_t lvgl_timerControlBlock;
const osTimerAttr_t lvgl_timer_attributes = {
  .name = "lvgl_timer",
  .cb_mem = &lvgl_timerControlBlock,
  .cb_size = sizeof(lvgl_timerControlBlock),
};
/* Definitions for buzzer_timer */
osTimerId_t buzzer_timerHandle;
osStaticTimerDef_t buzzer_timerControlBlock;
const osTimerAttr_t buzzer_timer_attributes = {
  .name = "buzzer_timer",
  .cb_mem = &buzzer_timerControlBlock,
  .cb_size = sizeof(buzzer_timerControlBlock),
};
/* Definitions for battery_check_timer */
osTimerId_t battery_check_timerHandle;
osStaticTimerDef_t battery_check_timerControlBlock;
const osTimerAttr_t battery_check_timer_attributes = {
  .name = "battery_check_timer",
  .cb_mem = &battery_check_timerControlBlock,
  .cb_size = sizeof(battery_check_timerControlBlock),
};
/* Definitions for IMU_read_timer */
osTimerId_t IMU_read_timerHandle;
osStaticTimerDef_t IMU_read_timerControlBlock;
const osTimerAttr_t IMU_read_timer_attributes = {
  .name = "IMU_read_timer",
  .cb_mem = &IMU_read_timerControlBlock,
  .cb_size = sizeof(IMU_read_timerControlBlock),
};
/* Definitions for packet_tx_idle */
osSemaphoreId_t packet_tx_idleHandle;
const osSemaphoreAttr_t packet_tx_idle_attributes = {
  .name = "packet_tx_idle"
};
/* Definitions for packet_rx_not_empty */
osSemaphoreId_t packet_rx_not_emptyHandle;
const osSemaphoreAttr_t packet_rx_not_empty_attributes = {
  .name = "packet_rx_not_empty"
};
/* Definitions for mpu6050_data_ready */
osSemaphoreId_t mpu6050_data_readyHandle;
const osSemaphoreAttr_t mpu6050_data_ready_attributes = {
  .name = "mpu6050_data_ready"
};
/* Definitions for sbus_data_ready_01_ */
osSemaphoreId_t sbus_data_ready_01_Handle;
const osSemaphoreAttr_t sbus_data_ready_01__attributes = {
  .name = "sbus_data_ready_01_"
};
/* Definitions for spi_tx_finished */
osSemaphoreId_t spi_tx_finishedHandle;
const osSemaphoreAttr_t spi_tx_finished_attributes = {
  .name = "spi_tx_finished"
};
/* Definitions for bluetooth_tx_idle */
osSemaphoreId_t bluetooth_tx_idleHandle;
const osSemaphoreAttr_t bluetooth_tx_idle_attributes = {
  .name = "bluetooth_tx_idle"
};
/* Definitions for sbus_data_ready_event_ */
osEventFlagsId_t sbus_data_ready_event_Handle;
osStaticEventGroupDef_t sbus_data_ready_event_ControlBlock;
const osEventFlagsAttr_t sbus_data_ready_event__attributes = {
  .name = "sbus_data_ready_event_",
  .cb_mem = &sbus_data_ready_event_ControlBlock,
  .cb_size = sizeof(sbus_data_ready_event_ControlBlock),
};

void StartDefaultTask(void *argument);
void imu_task_entry(void *argument);
void packet_tx_task_entry(void *argument);
void packet_rx_task_entry(void *argument);
void sbus_rx_task_entry(void *argument);
void gui_task_entry(void *argument);
void app_task_entry(void *argument);
void bluetooth_task_entry(void *argument);
void button_timer_callback(void *argument);
void led_timer_callback(void *argument);
void lvgl_timer_callback(void *argument);
void buzzer_timer_callback(void *argument);
void battery_check_timer_callback(void *argument);
void IMU_read_timer_callback(void *argument);

extern void MX_USB_HOST_Init(void);
void MX_FREERTOS_Init(void); /* (MISRA C 2004 rule 8.1) */

/* Hook prototypes */
void vApplicationIdleHook(void);
void vApplicationTickHook(void);

/* USER CODE BEGIN 2 */
void vApplicationIdleHook( void )
{
    /* vApplicationIdleHook() will only be called if configUSE_IDLE_HOOK is set
    to 1 in FreeRTOSConfig.h. It will be called on each iteration of the idle
    task. It is essential that code added to this hook function never attempts
    to block in any way (for example, call xQueueReceive() with a block time
    specified, or call vTaskDelay()). If the application makes use of the
    vTaskDelete() API function (as this demo application does) then it is also
    important that vApplicationIdleHook() is permitted to return to its calling
    function, because it is the responsibility of the idle task to clean up
    memory allocated by the kernel to any task that has since been deleted. */
}
/* USER CODE END 2 */

/* USER CODE BEGIN 3 */
void vApplicationTickHook( void )
{
    /* This function will be called by each tick interrupt if
    configUSE_TICK_HOOK is set to 1 in FreeRTOSConfig.h. User code can be
    added here, but the tick hook is called from an interrupt context, so
    code must not attempt to block, and only the interrupt safe FreeRTOS API
    functions can be used (those that end in FromISR()). */
    lv_tick_inc(1);
}
/* USER CODE END 3 */

void MX_FREERTOS_Init(void) {

  /* Create the semaphores(s) */
  /* creation of packet_tx_idle */
  packet_tx_idleHandle = osSemaphoreNew(1, 1, &packet_tx_idle_attributes);

  /* creation of packet_rx_not_empty */
  packet_rx_not_emptyHandle = osSemaphoreNew(1, 1, &packet_rx_not_empty_attributes);

  /* creation of mpu6050_data_ready */
  mpu6050_data_readyHandle = osSemaphoreNew(1, 1, &mpu6050_data_ready_attributes);

  /* creation of sbus_data_ready_01_ */
  sbus_data_ready_01_Handle = osSemaphoreNew(1, 1, &sbus_data_ready_01__attributes);

  /* creation of spi_tx_finished */
  spi_tx_finishedHandle = osSemaphoreNew(1, 1, &spi_tx_finished_attributes);

  /* creation of bluetooth_tx_idle */
  bluetooth_tx_idleHandle = osSemaphoreNew(1, 1, &bluetooth_tx_idle_attributes);

  /* Create the timer(s) */
  /* creation of button_timer */
  button_timerHandle = osTimerNew(button_timer_callback, osTimerPeriodic, NULL, &button_timer_attributes);

  /* creation of led_timer */
  led_timerHandle = osTimerNew(led_timer_callback, osTimerPeriodic, NULL, &led_timer_attributes);

  /* creation of lvgl_timer */
  lvgl_timerHandle = osTimerNew(lvgl_timer_callback, osTimerPeriodic, NULL, &lvgl_timer_attributes);

  /* creation of buzzer_timer */
  buzzer_timerHandle = osTimerNew(buzzer_timer_callback, osTimerPeriodic, NULL, &buzzer_timer_attributes);

  /* creation of battery_check_timer */
  battery_check_timerHandle = osTimerNew(battery_check_timer_callback, osTimerPeriodic, NULL, &battery_check_timer_attributes);

  /* creation of IMU_read_timer */
  IMU_read_timerHandle = osTimerNew(IMU_read_timer_callback, osTimerPeriodic, NULL, &IMU_read_timer_attributes);

  /* Create the queue(s) */
  /* creation of packet_tx_queue */
  packet_tx_queueHandle = osMessageQueueNew (64, sizeof(void*), &packet_tx_queue_attributes);

  /* creation of lvgl_event_queue */
  lvgl_event_queueHandle = osMessageQueueNew (16, sizeof(void*), &lvgl_event_queue_attributes);

  /* creation of moving_ctrl_queue */
  moving_ctrl_queueHandle = osMessageQueueNew (32, sizeof(char), &moving_ctrl_queue_attributes);

  /* creation of bluetooth_tx_queue */
  bluetooth_tx_queueHandle = osMessageQueueNew (8, 8, &bluetooth_tx_queue_attributes);

  /* Create the thread(s) */
  /* creation of defaultTask */
  defaultTaskHandle = osThreadNew(StartDefaultTask, NULL, &defaultTask_attributes);

  /* creation of imu_task */
  imu_taskHandle = osThreadNew(imu_task_entry, NULL, &imu_task_attributes);

  /* creation of packet_tx_task */
  packet_tx_taskHandle = osThreadNew(packet_tx_task_entry, NULL, &packet_tx_task_attributes);

  /* creation of packet_rx_task */
  packet_rx_taskHandle = osThreadNew(packet_rx_task_entry, NULL, &packet_rx_task_attributes);

  /* creation of sbus_rx_task */
  sbus_rx_taskHandle = osThreadNew(sbus_rx_task_entry, NULL, &sbus_rx_task_attributes);

  /* creation of gui_task */
  gui_taskHandle = osThreadNew(gui_task_entry, NULL, &gui_task_attributes);

  /* creation of app_task */
  app_taskHandle = osThreadNew(app_task_entry, NULL, &app_task_attributes);

  /* creation of bluetooth_task */
  bluetooth_taskHandle = osThreadNew(bluetooth_task_entry, NULL, &bluetooth_task_attributes);

  /* Create the event(s) */
  /* creation of sbus_data_ready_event_ */
  sbus_data_ready_event_Handle = osEventFlagsNew(&sbus_data_ready_event__attributes);

}

void StartDefaultTask(void *argument)
{
  /* init code for USB_HOST */
  MX_USB_HOST_Init();
    for(;;) {
        osDelay(1);
    }
}

__weak void imu_task_entry(void *argument)
{
    for(;;) {
        osDelay(1);
    }
}

__weak void packet_tx_task_entry(void *argument)
{
    for(;;) {
        osDelay(1);
    }
}

__weak void packet_rx_task_entry(void *argument)
{
    for(;;) {
        osDelay(1);
    }
}

__weak void sbus_rx_task_entry(void *argument)
{
    for(;;) {
        osDelay(1);
    }
}

__weak void gui_task_entry(void *argument)
{
  for(;;)
  {
    osDelay(1);
  }
}

__weak void app_task_entry(void *argument)
{
  for(;;)
  {
    osDelay(1);
  }
}

__weak void bluetooth_task_entry(void *argument)
{
  for(;;)
  {
    osDelay(1);
  }
}

/* button_timer_callback function */
__weak void button_timer_callback(void *argument)
{
}

/* led_timer_callback function */
__weak void led_timer_callback(void *argument)
{
}

/* lvgl_timer_callback function */
__weak void lvgl_timer_callback(void *argument)
{
}

/* buzzer_timer_callback function */
__weak void buzzer_timer_callback(void *argument)
{
}

/* battery_check_timer_callback function */
__weak void battery_check_timer_callback(void *argument)
{
}

/* IMU_read_timer_callback function */
__weak void IMU_read_timer_callback(void *argument)
{
}
